VERSION 5.7 ;
  NOWIREEXTENSIONATPIN ON ;
  DIVIDERCHAR "/" ;
  BUSBITCHARS "[]" ;
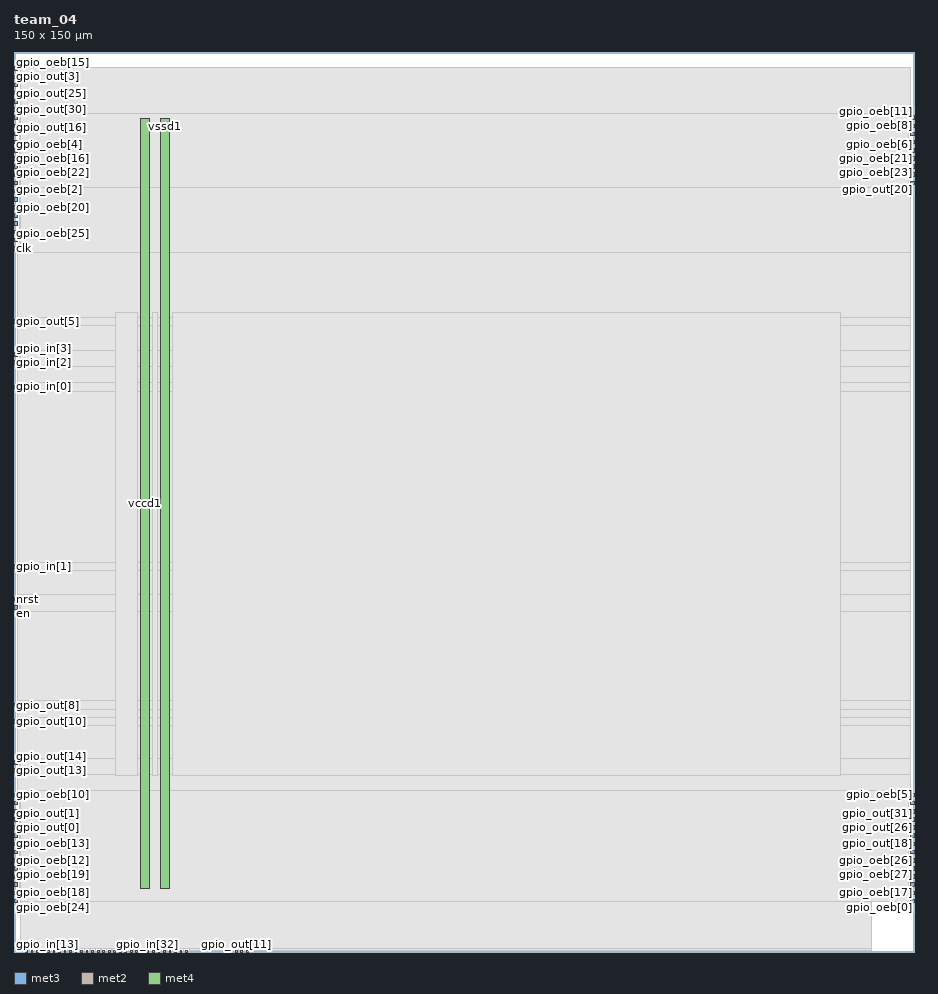
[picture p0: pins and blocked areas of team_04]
MACRO team_04
  CLASS BLOCK ;
  FOREIGN team_04 ;
  ORIGIN 0.000 0.000 ;
  SIZE 150.000 BY 150.000 ;
  PIN clk
    DIRECTION INPUT ;
    USE SIGNAL ;
    ANTENNAGATEAREA 1.286700 ;
    ANTENNADIFFAREA 0.434700 ;
    PORT
      LAYER met3 ;
        RECT 0.000 117.000 0.600 117.600 ;
    END
  END clk
  PIN en
    DIRECTION INPUT ;
    USE SIGNAL ;
    ANTENNAGATEAREA 0.647700 ;
    ANTENNADIFFAREA 0.434700 ;
    PORT
      LAYER met3 ;
        RECT 0.000 57.160 0.600 57.760 ;
    END
  END en
  PIN gpio_in[0]
    DIRECTION INPUT ;
    USE SIGNAL ;
    ANTENNAGATEAREA 0.647700 ;
    ANTENNADIFFAREA 0.434700 ;
    PORT
      LAYER met3 ;
        RECT 0.000 93.880 0.600 94.480 ;
    END
  END gpio_in[0]
  PIN gpio_in[10]
    DIRECTION INPUT ;
    USE SIGNAL ;
    PORT
      LAYER met2 ;
        RECT 1.930 0.000 2.210 0.280 ;
    END
  END gpio_in[10]
  PIN gpio_in[11]
    DIRECTION INPUT ;
    USE SIGNAL ;
    PORT
      LAYER met2 ;
        RECT 2.850 0.000 3.130 0.280 ;
    END
  END gpio_in[11]
  PIN gpio_in[12]
    DIRECTION INPUT ;
    USE SIGNAL ;
    PORT
      LAYER met2 ;
        RECT 3.770 0.000 4.050 0.280 ;
    END
  END gpio_in[12]
  PIN gpio_in[13]
    DIRECTION INPUT ;
    USE SIGNAL ;
    PORT
      LAYER met2 ;
        RECT 4.690 0.000 4.970 0.280 ;
    END
  END gpio_in[13]
  PIN gpio_in[14]
    DIRECTION INPUT ;
    USE SIGNAL ;
    PORT
      LAYER met2 ;
        RECT 5.610 0.000 5.890 0.280 ;
    END
  END gpio_in[14]
  PIN gpio_in[15]
    DIRECTION INPUT ;
    USE SIGNAL ;
    PORT
      LAYER met2 ;
        RECT 6.530 0.000 6.810 0.280 ;
    END
  END gpio_in[15]
  PIN gpio_in[16]
    DIRECTION INPUT ;
    USE SIGNAL ;
    PORT
      LAYER met2 ;
        RECT 7.450 0.000 7.730 0.280 ;
    END
  END gpio_in[16]
  PIN gpio_in[17]
    DIRECTION INPUT ;
    USE SIGNAL ;
    PORT
      LAYER met2 ;
        RECT 8.370 0.000 8.650 0.280 ;
    END
  END gpio_in[17]
  PIN gpio_in[18]
    DIRECTION INPUT ;
    USE SIGNAL ;
    PORT
      LAYER met2 ;
        RECT 9.290 0.000 9.570 0.280 ;
    END
  END gpio_in[18]
  PIN gpio_in[19]
    DIRECTION INPUT ;
    USE SIGNAL ;
    PORT
      LAYER met2 ;
        RECT 10.210 0.000 10.490 0.280 ;
    END
  END gpio_in[19]
  PIN gpio_in[1]
    DIRECTION INPUT ;
    USE SIGNAL ;
    ANTENNAGATEAREA 0.647700 ;
    ANTENNADIFFAREA 0.434700 ;
    PORT
      LAYER met3 ;
        RECT 0.000 63.960 0.600 64.560 ;
    END
  END gpio_in[1]
  PIN gpio_in[20]
    DIRECTION INPUT ;
    USE SIGNAL ;
    PORT
      LAYER met2 ;
        RECT 11.130 0.000 11.410 0.280 ;
    END
  END gpio_in[20]
  PIN gpio_in[21]
    DIRECTION INPUT ;
    USE SIGNAL ;
    PORT
      LAYER met2 ;
        RECT 12.050 0.000 12.330 0.280 ;
    END
  END gpio_in[21]
  PIN gpio_in[22]
    DIRECTION INPUT ;
    USE SIGNAL ;
    PORT
      LAYER met2 ;
        RECT 12.970 0.000 13.250 0.280 ;
    END
  END gpio_in[22]
  PIN gpio_in[23]
    DIRECTION INPUT ;
    USE SIGNAL ;
    PORT
      LAYER met2 ;
        RECT 13.890 0.000 14.170 0.280 ;
    END
  END gpio_in[23]
  PIN gpio_in[24]
    DIRECTION INPUT ;
    USE SIGNAL ;
    PORT
      LAYER met2 ;
        RECT 14.810 0.000 15.090 0.280 ;
    END
  END gpio_in[24]
  PIN gpio_in[25]
    DIRECTION INPUT ;
    USE SIGNAL ;
    PORT
      LAYER met2 ;
        RECT 15.730 0.000 16.010 0.280 ;
    END
  END gpio_in[25]
  PIN gpio_in[26]
    DIRECTION INPUT ;
    USE SIGNAL ;
    PORT
      LAYER met2 ;
        RECT 16.650 0.000 16.930 0.280 ;
    END
  END gpio_in[26]
  PIN gpio_in[27]
    DIRECTION INPUT ;
    USE SIGNAL ;
    PORT
      LAYER met2 ;
        RECT 17.570 0.000 17.850 0.280 ;
    END
  END gpio_in[27]
  PIN gpio_in[28]
    DIRECTION INPUT ;
    USE SIGNAL ;
    PORT
      LAYER met2 ;
        RECT 18.490 0.000 18.770 0.280 ;
    END
  END gpio_in[28]
  PIN gpio_in[29]
    DIRECTION INPUT ;
    USE SIGNAL ;
    PORT
      LAYER met2 ;
        RECT 19.410 0.000 19.690 0.280 ;
    END
  END gpio_in[29]
  PIN gpio_in[2]
    DIRECTION INPUT ;
    USE SIGNAL ;
    ANTENNAGATEAREA 0.647700 ;
    ANTENNADIFFAREA 0.434700 ;
    PORT
      LAYER met3 ;
        RECT 0.000 97.960 0.600 98.560 ;
    END
  END gpio_in[2]
  PIN gpio_in[30]
    DIRECTION INPUT ;
    USE SIGNAL ;
    PORT
      LAYER met2 ;
        RECT 20.330 0.000 20.610 0.280 ;
    END
  END gpio_in[30]
  PIN gpio_in[31]
    DIRECTION INPUT ;
    USE SIGNAL ;
    PORT
      LAYER met2 ;
        RECT 21.250 0.000 21.530 0.280 ;
    END
  END gpio_in[31]
  PIN gpio_in[32]
    DIRECTION INPUT ;
    USE SIGNAL ;
    PORT
      LAYER met2 ;
        RECT 22.170 0.000 22.450 0.280 ;
    END
  END gpio_in[32]
  PIN gpio_in[33]
    DIRECTION INPUT ;
    USE SIGNAL ;
    PORT
      LAYER met2 ;
        RECT 23.090 0.000 23.370 0.280 ;
    END
  END gpio_in[33]
  PIN gpio_in[3]
    DIRECTION INPUT ;
    USE SIGNAL ;
    ANTENNAGATEAREA 0.647700 ;
    ANTENNADIFFAREA 0.434700 ;
    PORT
      LAYER met3 ;
        RECT 0.000 99.320 0.600 99.920 ;
    END
  END gpio_in[3]
  PIN gpio_in[4]
    DIRECTION INPUT ;
    USE SIGNAL ;
    PORT
      LAYER met2 ;
        RECT 24.010 0.000 24.290 0.280 ;
    END
  END gpio_in[4]
  PIN gpio_in[5]
    DIRECTION INPUT ;
    USE SIGNAL ;
    PORT
      LAYER met2 ;
        RECT 24.930 0.000 25.210 0.280 ;
    END
  END gpio_in[5]
  PIN gpio_in[6]
    DIRECTION INPUT ;
    USE SIGNAL ;
    PORT
      LAYER met2 ;
        RECT 25.850 0.000 26.130 0.280 ;
    END
  END gpio_in[6]
  PIN gpio_in[7]
    DIRECTION INPUT ;
    USE SIGNAL ;
    PORT
      LAYER met2 ;
        RECT 26.770 0.000 27.050 0.280 ;
    END
  END gpio_in[7]
  PIN gpio_in[8]
    DIRECTION INPUT ;
    USE SIGNAL ;
    PORT
      LAYER met2 ;
        RECT 27.690 0.000 27.970 0.280 ;
    END
  END gpio_in[8]
  PIN gpio_in[9]
    DIRECTION INPUT ;
    USE SIGNAL ;
    PORT
      LAYER met2 ;
        RECT 28.610 0.000 28.890 0.280 ;
    END
  END gpio_in[9]
  PIN gpio_oeb[0]
    DIRECTION OUTPUT ;
    USE SIGNAL ;
    PORT
      LAYER met3 ;
        RECT 149.400 8.200 150.000 8.800 ;
    END
  END gpio_oeb[0]
  PIN gpio_oeb[10]
    DIRECTION OUTPUT ;
    USE SIGNAL ;
    PORT
      LAYER met3 ;
        RECT 0.000 25.880 0.600 26.480 ;
    END
  END gpio_oeb[10]
  PIN gpio_oeb[11]
    DIRECTION OUTPUT ;
    USE SIGNAL ;
    PORT
      LAYER met3 ;
        RECT 149.400 138.760 150.000 139.360 ;
    END
  END gpio_oeb[11]
  PIN gpio_oeb[12]
    DIRECTION OUTPUT ;
    USE SIGNAL ;
    PORT
      LAYER met3 ;
        RECT 0.000 15.000 0.600 15.600 ;
    END
  END gpio_oeb[12]
  PIN gpio_oeb[13]
    DIRECTION OUTPUT ;
    USE SIGNAL ;
    PORT
      LAYER met3 ;
        RECT 0.000 17.720 0.600 18.320 ;
    END
  END gpio_oeb[13]
  PIN gpio_oeb[14]
    DIRECTION OUTPUT ;
    USE SIGNAL ;
    PORT
      LAYER met3 ;
        RECT 0.000 19.080 0.600 19.680 ;
    END
  END gpio_oeb[14]
  PIN gpio_oeb[15]
    DIRECTION OUTPUT ;
    USE SIGNAL ;
    PORT
      LAYER met3 ;
        RECT 0.000 146.920 0.600 147.520 ;
    END
  END gpio_oeb[15]
  PIN gpio_oeb[16]
    DIRECTION OUTPUT ;
    USE SIGNAL ;
    PORT
      LAYER met3 ;
        RECT 0.000 131.960 0.600 132.560 ;
    END
  END gpio_oeb[16]
  PIN gpio_oeb[17]
    DIRECTION OUTPUT ;
    USE SIGNAL ;
    PORT
      LAYER met3 ;
        RECT 149.400 9.560 150.000 10.160 ;
    END
  END gpio_oeb[17]
  PIN gpio_oeb[18]
    DIRECTION OUTPUT ;
    USE SIGNAL ;
    PORT
      LAYER met3 ;
        RECT 0.000 9.560 0.600 10.160 ;
    END
  END gpio_oeb[18]
  PIN gpio_oeb[19]
    DIRECTION OUTPUT ;
    USE SIGNAL ;
    PORT
      LAYER met3 ;
        RECT 0.000 13.640 0.600 14.240 ;
    END
  END gpio_oeb[19]
  PIN gpio_oeb[1]
    DIRECTION OUTPUT ;
    USE SIGNAL ;
    PORT
      LAYER met3 ;
        RECT 0.000 12.280 0.600 12.880 ;
    END
  END gpio_oeb[1]
  PIN gpio_oeb[20]
    DIRECTION OUTPUT ;
    USE SIGNAL ;
    PORT
      LAYER met3 ;
        RECT 0.000 123.800 0.600 124.400 ;
    END
  END gpio_oeb[20]
  PIN gpio_oeb[21]
    DIRECTION OUTPUT ;
    USE SIGNAL ;
    PORT
      LAYER met3 ;
        RECT 149.400 131.960 150.000 132.560 ;
    END
  END gpio_oeb[21]
  PIN gpio_oeb[22]
    DIRECTION OUTPUT ;
    USE SIGNAL ;
    PORT
      LAYER met3 ;
        RECT 0.000 130.600 0.600 131.200 ;
    END
  END gpio_oeb[22]
  PIN gpio_oeb[23]
    DIRECTION OUTPUT ;
    USE SIGNAL ;
    PORT
      LAYER met3 ;
        RECT 149.400 130.600 150.000 131.200 ;
    END
  END gpio_oeb[23]
  PIN gpio_oeb[24]
    DIRECTION OUTPUT ;
    USE SIGNAL ;
    PORT
      LAYER met3 ;
        RECT 0.000 8.200 0.600 8.800 ;
    END
  END gpio_oeb[24]
  PIN gpio_oeb[25]
    DIRECTION OUTPUT ;
    USE SIGNAL ;
    PORT
      LAYER met3 ;
        RECT 0.000 118.360 0.600 118.960 ;
    END
  END gpio_oeb[25]
  PIN gpio_oeb[26]
    DIRECTION OUTPUT ;
    USE SIGNAL ;
    PORT
      LAYER met3 ;
        RECT 149.400 15.000 150.000 15.600 ;
    END
  END gpio_oeb[26]
  PIN gpio_oeb[27]
    DIRECTION OUTPUT ;
    USE SIGNAL ;
    PORT
      LAYER met3 ;
        RECT 149.400 13.640 150.000 14.240 ;
    END
  END gpio_oeb[27]
  PIN gpio_oeb[28]
    DIRECTION OUTPUT ;
    USE SIGNAL ;
    PORT
      LAYER met3 ;
        RECT 0.000 122.440 0.600 123.040 ;
    END
  END gpio_oeb[28]
  PIN gpio_oeb[29]
    DIRECTION OUTPUT ;
    USE SIGNAL ;
    PORT
      LAYER met3 ;
        RECT 0.000 125.160 0.600 125.760 ;
    END
  END gpio_oeb[29]
  PIN gpio_oeb[2]
    DIRECTION OUTPUT ;
    USE SIGNAL ;
    PORT
      LAYER met3 ;
        RECT 0.000 127.880 0.600 128.480 ;
    END
  END gpio_oeb[2]
  PIN gpio_oeb[30]
    DIRECTION OUTPUT ;
    USE SIGNAL ;
    PORT
      LAYER met3 ;
        RECT 149.400 12.280 150.000 12.880 ;
    END
  END gpio_oeb[30]
  PIN gpio_oeb[31]
    DIRECTION OUTPUT ;
    USE SIGNAL ;
    PORT
      LAYER met3 ;
        RECT 149.400 129.240 150.000 129.840 ;
    END
  END gpio_oeb[31]
  PIN gpio_oeb[32]
    DIRECTION OUTPUT ;
    USE SIGNAL ;
    PORT
      LAYER met3 ;
        RECT 0.000 121.080 0.600 121.680 ;
    END
  END gpio_oeb[32]
  PIN gpio_oeb[33]
    DIRECTION OUTPUT ;
    USE SIGNAL ;
    PORT
      LAYER met3 ;
        RECT 0.000 126.520 0.600 127.120 ;
    END
  END gpio_oeb[33]
  PIN gpio_oeb[3]
    DIRECTION OUTPUT ;
    USE SIGNAL ;
    PORT
      LAYER met3 ;
        RECT 149.400 10.920 150.000 11.520 ;
    END
  END gpio_oeb[3]
  PIN gpio_oeb[4]
    DIRECTION OUTPUT ;
    USE SIGNAL ;
    PORT
      LAYER met3 ;
        RECT 0.000 133.320 0.600 133.920 ;
    END
  END gpio_oeb[4]
  PIN gpio_oeb[5]
    DIRECTION OUTPUT ;
    USE SIGNAL ;
    PORT
      LAYER met3 ;
        RECT 149.400 25.880 150.000 26.480 ;
    END
  END gpio_oeb[5]
  PIN gpio_oeb[6]
    DIRECTION OUTPUT ;
    USE SIGNAL ;
    PORT
      LAYER met3 ;
        RECT 149.400 133.320 150.000 133.920 ;
    END
  END gpio_oeb[6]
  PIN gpio_oeb[7]
    DIRECTION OUTPUT ;
    USE SIGNAL ;
    PORT
      LAYER met3 ;
        RECT 0.000 134.680 0.600 135.280 ;
    END
  END gpio_oeb[7]
  PIN gpio_oeb[8]
    DIRECTION OUTPUT ;
    USE SIGNAL ;
    PORT
      LAYER met3 ;
        RECT 149.400 137.400 150.000 138.000 ;
    END
  END gpio_oeb[8]
  PIN gpio_oeb[9]
    DIRECTION OUTPUT ;
    USE SIGNAL ;
    PORT
      LAYER met3 ;
        RECT 149.400 134.680 150.000 135.280 ;
    END
  END gpio_oeb[9]
  PIN gpio_out[0]
    DIRECTION OUTPUT ;
    USE SIGNAL ;
    PORT
      LAYER met3 ;
        RECT 0.000 20.440 0.600 21.040 ;
    END
  END gpio_out[0]
  PIN gpio_out[10]
    DIRECTION OUTPUT ;
    USE SIGNAL ;
    ANTENNADIFFAREA 0.702900 ;
    PORT
      LAYER met3 ;
        RECT 0.000 38.120 0.600 38.720 ;
    END
  END gpio_out[10]
  PIN gpio_out[11]
    DIRECTION OUTPUT ;
    USE SIGNAL ;
    ANTENNADIFFAREA 0.702900 ;
    PORT
      LAYER met2 ;
        RECT 36.890 0.000 37.170 0.280 ;
    END
  END gpio_out[11]
  PIN gpio_out[12]
    DIRECTION OUTPUT ;
    USE SIGNAL ;
    ANTENNADIFFAREA 0.702900 ;
    PORT
      LAYER met2 ;
        RECT 35.970 0.000 36.250 0.280 ;
    END
  END gpio_out[12]
  PIN gpio_out[13]
    DIRECTION OUTPUT ;
    USE SIGNAL ;
    ANTENNADIFFAREA 0.702900 ;
    PORT
      LAYER met3 ;
        RECT 0.000 29.960 0.600 30.560 ;
    END
  END gpio_out[13]
  PIN gpio_out[14]
    DIRECTION OUTPUT ;
    USE SIGNAL ;
    ANTENNADIFFAREA 0.702900 ;
    PORT
      LAYER met3 ;
        RECT 0.000 31.320 0.600 31.920 ;
    END
  END gpio_out[14]
  PIN gpio_out[15]
    DIRECTION OUTPUT ;
    USE SIGNAL ;
    PORT
      LAYER met3 ;
        RECT 0.000 129.240 0.600 129.840 ;
    END
  END gpio_out[15]
  PIN gpio_out[16]
    DIRECTION OUTPUT ;
    USE SIGNAL ;
    PORT
      LAYER met3 ;
        RECT 0.000 136.040 0.600 136.640 ;
    END
  END gpio_out[16]
  PIN gpio_out[17]
    DIRECTION OUTPUT ;
    USE SIGNAL ;
    PORT
      LAYER met3 ;
        RECT 149.400 24.520 150.000 25.120 ;
    END
  END gpio_out[17]
  PIN gpio_out[18]
    DIRECTION OUTPUT ;
    USE SIGNAL ;
    PORT
      LAYER met3 ;
        RECT 149.400 17.720 150.000 18.320 ;
    END
  END gpio_out[18]
  PIN gpio_out[19]
    DIRECTION OUTPUT ;
    USE SIGNAL ;
    PORT
      LAYER met3 ;
        RECT 149.400 19.080 150.000 19.680 ;
    END
  END gpio_out[19]
  PIN gpio_out[1]
    DIRECTION OUTPUT ;
    USE SIGNAL ;
    PORT
      LAYER met3 ;
        RECT 0.000 21.800 0.600 22.400 ;
    END
  END gpio_out[1]
  PIN gpio_out[20]
    DIRECTION OUTPUT ;
    USE SIGNAL ;
    PORT
      LAYER met3 ;
        RECT 149.400 127.880 150.000 128.480 ;
    END
  END gpio_out[20]
  PIN gpio_out[21]
    DIRECTION OUTPUT ;
    USE SIGNAL ;
    PORT
      LAYER met3 ;
        RECT 0.000 23.160 0.600 23.760 ;
    END
  END gpio_out[21]
  PIN gpio_out[22]
    DIRECTION OUTPUT ;
    USE SIGNAL ;
    PORT
      LAYER met3 ;
        RECT 0.000 137.400 0.600 138.000 ;
    END
  END gpio_out[22]
  PIN gpio_out[23]
    DIRECTION OUTPUT ;
    USE SIGNAL ;
    PORT
      LAYER met3 ;
        RECT 0.000 138.760 0.600 139.360 ;
    END
  END gpio_out[23]
  PIN gpio_out[24]
    DIRECTION OUTPUT ;
    USE SIGNAL ;
    PORT
      LAYER met3 ;
        RECT 0.000 141.480 0.600 142.080 ;
    END
  END gpio_out[24]
  PIN gpio_out[25]
    DIRECTION OUTPUT ;
    USE SIGNAL ;
    PORT
      LAYER met3 ;
        RECT 0.000 142.840 0.600 143.440 ;
    END
  END gpio_out[25]
  PIN gpio_out[26]
    DIRECTION OUTPUT ;
    USE SIGNAL ;
    PORT
      LAYER met3 ;
        RECT 149.400 20.440 150.000 21.040 ;
    END
  END gpio_out[26]
  PIN gpio_out[27]
    DIRECTION OUTPUT ;
    USE SIGNAL ;
    PORT
      LAYER met3 ;
        RECT 149.400 23.160 150.000 23.760 ;
    END
  END gpio_out[27]
  PIN gpio_out[28]
    DIRECTION OUTPUT ;
    USE SIGNAL ;
    PORT
      LAYER met3 ;
        RECT 149.400 136.040 150.000 136.640 ;
    END
  END gpio_out[28]
  PIN gpio_out[29]
    DIRECTION OUTPUT ;
    USE SIGNAL ;
    PORT
      LAYER met3 ;
        RECT 0.000 24.520 0.600 25.120 ;
    END
  END gpio_out[29]
  PIN gpio_out[2]
    DIRECTION OUTPUT ;
    USE SIGNAL ;
    PORT
      LAYER met3 ;
        RECT 0.000 16.360 0.600 16.960 ;
    END
  END gpio_out[2]
  PIN gpio_out[30]
    DIRECTION OUTPUT ;
    USE SIGNAL ;
    PORT
      LAYER met3 ;
        RECT 0.000 140.120 0.600 140.720 ;
    END
  END gpio_out[30]
  PIN gpio_out[31]
    DIRECTION OUTPUT ;
    USE SIGNAL ;
    PORT
      LAYER met3 ;
        RECT 149.400 21.800 150.000 22.400 ;
    END
  END gpio_out[31]
  PIN gpio_out[32]
    DIRECTION OUTPUT ;
    USE SIGNAL ;
    PORT
      LAYER met3 ;
        RECT 0.000 144.200 0.600 144.800 ;
    END
  END gpio_out[32]
  PIN gpio_out[33]
    DIRECTION OUTPUT ;
    USE SIGNAL ;
    PORT
      LAYER met3 ;
        RECT 149.400 16.360 150.000 16.960 ;
    END
  END gpio_out[33]
  PIN gpio_out[3]
    DIRECTION OUTPUT ;
    USE SIGNAL ;
    PORT
      LAYER met3 ;
        RECT 0.000 145.560 0.600 146.160 ;
    END
  END gpio_out[3]
  PIN gpio_out[4]
    DIRECTION OUTPUT ;
    USE SIGNAL ;
    ANTENNADIFFAREA 0.702900 ;
    PORT
      LAYER met2 ;
        RECT 38.730 0.000 39.010 0.280 ;
    END
  END gpio_out[4]
  PIN gpio_out[5]
    DIRECTION OUTPUT ;
    USE SIGNAL ;
    ANTENNADIFFAREA 0.702900 ;
    PORT
      LAYER met3 ;
        RECT 0.000 104.760 0.600 105.360 ;
    END
  END gpio_out[5]
  PIN gpio_out[6]
    DIRECTION OUTPUT ;
    USE SIGNAL ;
    PORT
      LAYER met3 ;
        RECT 0.000 10.920 0.600 11.520 ;
    END
  END gpio_out[6]
  PIN gpio_out[7]
    DIRECTION OUTPUT ;
    USE SIGNAL ;
    PORT
      LAYER met3 ;
        RECT 0.000 119.720 0.600 120.320 ;
    END
  END gpio_out[7]
  PIN gpio_out[8]
    DIRECTION OUTPUT ;
    USE SIGNAL ;
    ANTENNADIFFAREA 0.702900 ;
    PORT
      LAYER met3 ;
        RECT 0.000 40.840 0.600 41.440 ;
    END
  END gpio_out[8]
  PIN gpio_out[9]
    DIRECTION OUTPUT ;
    USE SIGNAL ;
    ANTENNADIFFAREA 0.702900 ;
    PORT
      LAYER met2 ;
        RECT 37.810 0.000 38.090 0.280 ;
    END
  END gpio_out[9]
  PIN nrst
    DIRECTION INPUT ;
    USE SIGNAL ;
    ANTENNAGATEAREA 0.647700 ;
    ANTENNADIFFAREA 0.434700 ;
    PORT
      LAYER met3 ;
        RECT 0.000 58.520 0.600 59.120 ;
    END
  END nrst
  PIN vccd1
    DIRECTION INOUT ;
    USE POWER ;
    PORT
      LAYER met4 ;
        RECT 21.040 10.640 22.640 138.960 ;
    END
  END vccd1
  PIN vssd1
    DIRECTION INOUT ;
    USE GROUND ;
    PORT
      LAYER met4 ;
        RECT 24.340 10.640 25.940 138.960 ;
    END
  END vssd1
  OBS
      LAYER nwell ;
        RECT 5.330 10.760 144.630 138.910 ;
      LAYER li1 ;
        RECT 5.520 10.795 144.440 138.805 ;
      LAYER met1 ;
        RECT 0.990 10.640 144.440 138.960 ;
      LAYER met2 ;
        RECT 1.010 0.560 142.970 147.405 ;
        RECT 1.010 0.280 1.650 0.560 ;
        RECT 2.490 0.280 2.570 0.560 ;
        RECT 3.410 0.280 3.490 0.560 ;
        RECT 4.330 0.280 4.410 0.560 ;
        RECT 5.250 0.280 5.330 0.560 ;
        RECT 6.170 0.280 6.250 0.560 ;
        RECT 7.090 0.280 7.170 0.560 ;
        RECT 8.010 0.280 8.090 0.560 ;
        RECT 8.930 0.280 9.010 0.560 ;
        RECT 9.850 0.280 9.930 0.560 ;
        RECT 10.770 0.280 10.850 0.560 ;
        RECT 11.690 0.280 11.770 0.560 ;
        RECT 12.610 0.280 12.690 0.560 ;
        RECT 13.530 0.280 13.610 0.560 ;
        RECT 14.450 0.280 14.530 0.560 ;
        RECT 15.370 0.280 15.450 0.560 ;
        RECT 16.290 0.280 16.370 0.560 ;
        RECT 17.210 0.280 17.290 0.560 ;
        RECT 18.130 0.280 18.210 0.560 ;
        RECT 19.050 0.280 19.130 0.560 ;
        RECT 19.970 0.280 20.050 0.560 ;
        RECT 20.890 0.280 20.970 0.560 ;
        RECT 21.810 0.280 21.890 0.560 ;
        RECT 22.730 0.280 22.810 0.560 ;
        RECT 23.650 0.280 23.730 0.560 ;
        RECT 24.570 0.280 24.650 0.560 ;
        RECT 25.490 0.280 25.570 0.560 ;
        RECT 26.410 0.280 26.490 0.560 ;
        RECT 27.330 0.280 27.410 0.560 ;
        RECT 28.250 0.280 28.330 0.560 ;
        RECT 29.170 0.280 35.690 0.560 ;
        RECT 36.530 0.280 36.610 0.560 ;
        RECT 37.450 0.280 37.530 0.560 ;
        RECT 38.370 0.280 38.450 0.560 ;
        RECT 39.290 0.280 142.970 0.560 ;
      LAYER met3 ;
        RECT 1.000 139.760 149.400 147.385 ;
        RECT 1.000 127.480 149.000 139.760 ;
        RECT 1.000 116.600 149.400 127.480 ;
        RECT 0.600 105.760 149.400 116.600 ;
        RECT 1.000 104.360 149.400 105.760 ;
        RECT 0.600 100.320 149.400 104.360 ;
        RECT 1.000 97.560 149.400 100.320 ;
        RECT 0.600 94.880 149.400 97.560 ;
        RECT 1.000 93.480 149.400 94.880 ;
        RECT 0.600 64.960 149.400 93.480 ;
        RECT 1.000 63.560 149.400 64.960 ;
        RECT 0.600 59.520 149.400 63.560 ;
        RECT 1.000 56.760 149.400 59.520 ;
        RECT 0.600 41.840 149.400 56.760 ;
        RECT 1.000 40.440 149.400 41.840 ;
        RECT 0.600 39.120 149.400 40.440 ;
        RECT 1.000 37.720 149.400 39.120 ;
        RECT 0.600 32.320 149.400 37.720 ;
        RECT 1.000 29.560 149.400 32.320 ;
        RECT 0.600 26.880 149.400 29.560 ;
        RECT 1.000 8.335 149.000 26.880 ;
      LAYER met4 ;
        RECT 16.855 29.415 20.640 106.585 ;
        RECT 23.040 29.415 23.940 106.585 ;
        RECT 26.340 29.415 137.705 106.585 ;
  END
END team_04
END LIBRARY

